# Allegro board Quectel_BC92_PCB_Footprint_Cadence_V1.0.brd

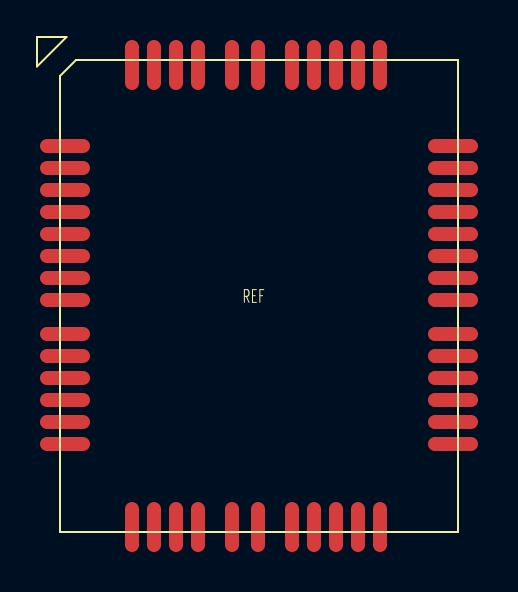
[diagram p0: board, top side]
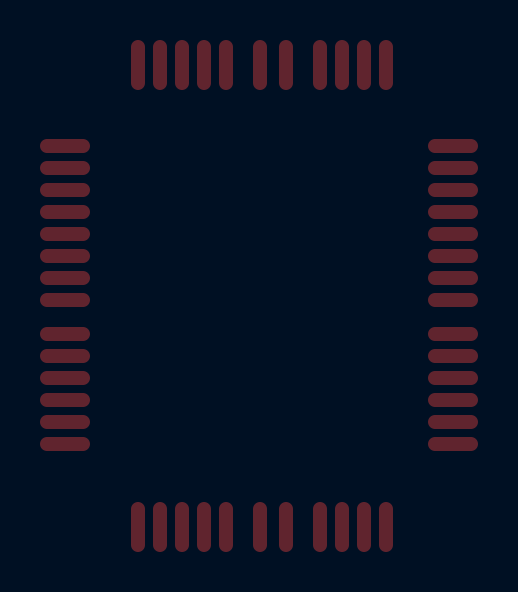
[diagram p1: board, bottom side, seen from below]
No outline. copper layers: TOP, BOTTOM. Coordinates in mm from the lowest, leftmost part position.

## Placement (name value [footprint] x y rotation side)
REF  -  [unnamed]  0 0 0 top

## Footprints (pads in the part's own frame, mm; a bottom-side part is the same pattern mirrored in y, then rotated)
unnamed
  oval 2.5x0.7 smd: 1(-9.7,7.5) 2(-9.7,6.4) 3(-9.7,5.3) 4(-9.7,4.2) 5(-9.7,3.1) 6(-9.7,-1.9) 7(-9.7,-3) 8(-9.7,-4.1) 9(-9.7,-5.2) 10(-9.7,-6.3) 11(-9.7,-7.4) 21(9.7,-7.4) 22(9.7,-6.3) 23(9.7,-5.2) 24(9.7,-4.1) 25(9.7,-3) 26(9.7,-1.9) 27(9.7,3.1) 28(9.7,4.2) 29(9.7,5.3) 30(9.7,6.4) 31(9.7,7.5) 43(9.7,-0.2) 44(9.7,0.9) 45(9.7,2) 48(-9.7,2) 49(-9.7,0.9) 50(-9.7,-0.2)
  oval 0.7x2.5 smd: 12(-6.35,-11.55) 13(-5.25,-11.55) 14(-4.15,-11.55) 15(-3.05,-11.55) 16(1.65,-11.55) 17(2.75,-11.55) 18(3.85,-11.55) 19(4.95,-11.55) 20(6.05,-11.55) 32(6.05,11.55) 33(4.95,11.55) 34(3.85,11.55) 35(2.75,11.55) 36(1.65,11.55) 37(-3.05,11.55) 38(-4.15,11.55) 39(-5.25,11.55) 40(-6.35,11.55) 41(-1.35,-11.55) 42(-0.05,-11.55) 46(-0.05,11.55) 47(-1.35,11.55)

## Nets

Pads without a net: REF 1 2 3 4 5 6 7 8 9 10 11 12 13 14 15 16 17 18 19 20 21 22 23 24 25 26 27 28 29 30 31 32 33 34 35 36 37 38 39 40 41 42 43 44 45 46 47 48 49 50
